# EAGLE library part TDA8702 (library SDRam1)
Video-DAC Philips

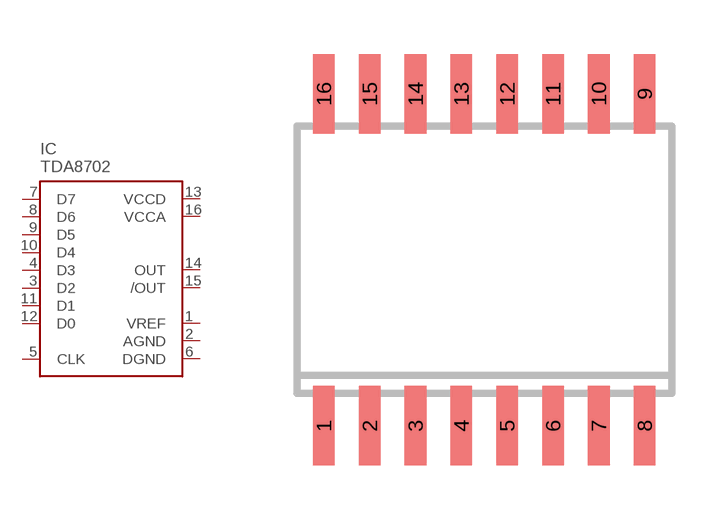
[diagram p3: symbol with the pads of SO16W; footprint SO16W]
Designator prefix IC

## TDA8702  [SO16W]
1  VREF
2  AGND
3  D2
4  D3
5  CLK
6  DGND
7  D7
8  D6
9  D5
10  D4
11  D1
12  D0
13  VCCD
14  OUT
15  /OUT
16  VCCA

## Footprint SO16W (pad centres in mm)
SMALL OUTLINE INTEGRATED CIRCUIT wide body 7.5 mm/JEDEC MS-013AA
smd 0.6 x 2.2: 1 -4.445,-4.6; 2 -3.175,-4.6; 3 -1.905,-4.6; 4 -0.635,-4.6; 5 0.635,-4.6; 6 1.905,-4.6; 7 3.175,-4.6; 8 4.445,-4.6; 9 4.445,4.6; 10 3.175,4.6; 11 1.905,4.6; 12 0.635,4.6; 13 -0.635,4.6; 14 -1.905,4.6; 15 -3.175,4.6; 16 -4.445,4.6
